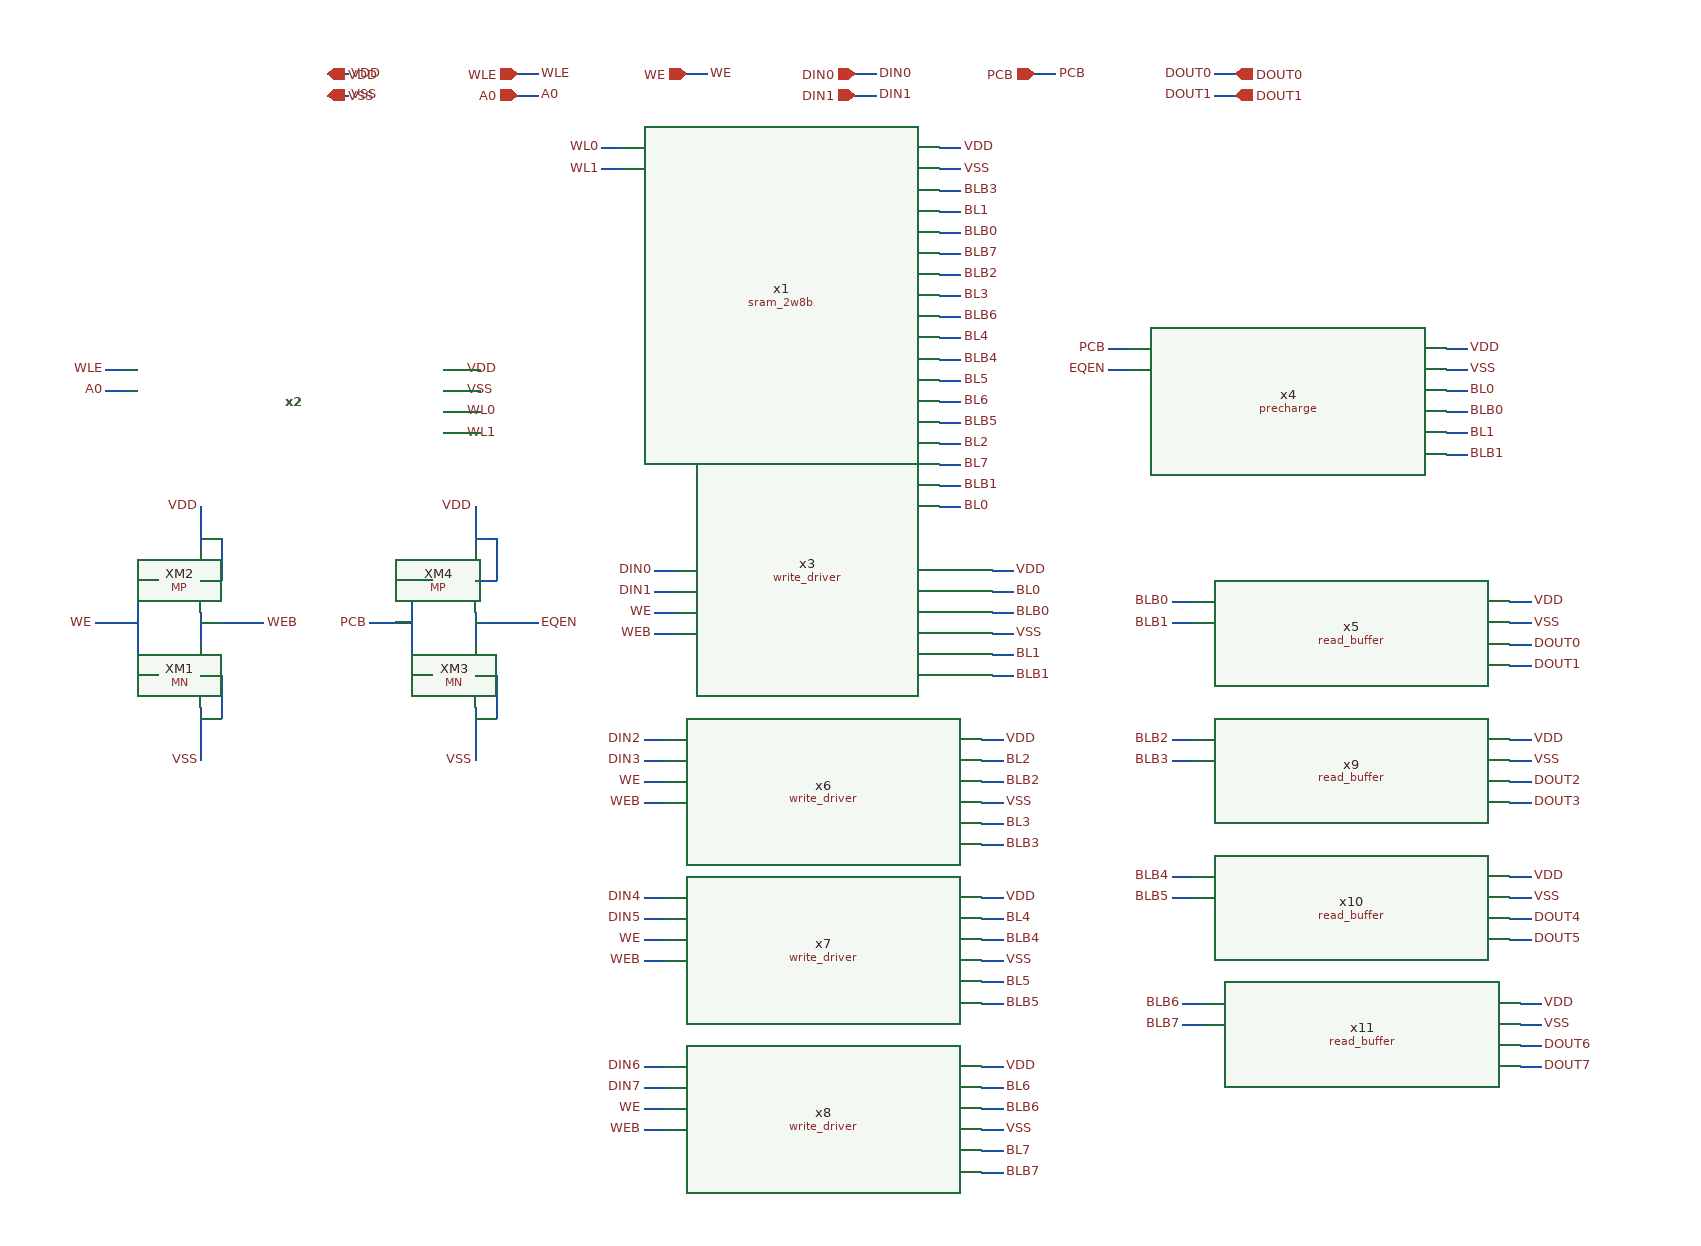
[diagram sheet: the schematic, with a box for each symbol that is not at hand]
v {xschem version=3.4.8RC file_version=1.3}
G {}
K {}
V {}
S {}
F {}
E {}
N 150 -410 170 -410 {lab=A0}
N 150 -430 170 -430 {lab=WLE}
N 470 -430 490 -430 {lab=VDD}
N 470 -410 490 -410 {lab=VSS}
N 470 -390 490 -390 {lab=WL0}
N 470 -370 490 -370 {lab=WL1}
N 620 -640 640 -640 {lab=WL0}
N 620 -620 640 -620 {lab=WL1}
N 940 -300 960 -300 {lab=BL0}
N 940 -580 960 -580 {lab=BL1}
N 940 -320 960 -320 {lab=BLB1}
N 940 -560 960 -560 {lab=BLB0}
N 1100 -450 1120 -450 {lab=PCB}
N 1100 -430 1120 -430 {lab=EQEN}
N 670 -240 690 -240 {lab=DIN0}
N 670 -220 690 -220 {lab=DIN1}
N 670 -200 690 -200 {lab=WE}
N 670 -180 690 -180 {lab=WEB}
N 990 -240 1010 -240 {lab=VDD}
N 990 -220 1010 -220 {lab=BL0}
N 990 -200 1010 -200 {lab=BLB0}
N 990 -180 1010 -180 {lab=VSS}
N 990 -160 1010 -160 {lab=BL1}
N 990 -140 1010 -140 {lab=BLB1}
N 1160 -210 1180 -210 {lab=BLB0}
N 1160 -190 1180 -190 {lab=BLB1}
N 1420 -450 1440 -450 {lab=VDD}
N 1420 -430 1440 -430 {lab=VSS}
N 1420 -410 1440 -410 {lab=BL0}
N 1420 -390 1440 -390 {lab=BLB0}
N 1420 -370 1440 -370 {lab=BL1}
N 1420 -350 1440 -350 {lab=BLB1}
N 1480 -210 1500 -210 {lab=VDD}
N 1480 -190 1500 -190 {lab=VSS}
N 1480 -170 1500 -170 {lab=DOUT0}
N 1480 -150 1500 -150 {lab=DOUT1}
N 360 -710 380 -710 {lab=VDD}
N 360 -690 380 -690 {lab=VSS}
N 540 -710 560 -710 {lab=WLE}
N 540 -690 560 -690 {lab=A0}
N 700 -710 720 -710 {lab=WE}
N 860 -710 880 -710 {lab=DIN0}
N 860 -690 880 -690 {lab=DIN1}
N 1030 -710 1050 -710 {lab=PCB}
N 1200 -710 1220 -710 {lab=DOUT0}
N 1200 -690 1220 -690 {lab=DOUT1}
N 240 -200 240 -170 {lab=WEB}
N 240 -110 240 -60 {lab=VSS}
N 240 -140 260 -140 {lab=VSS}
N 260 -140 260 -100 {lab=VSS}
N 240 -100 260 -100 {lab=VSS}
N 240 -300 240 -260 {lab=VDD}
N 180 -230 200 -230 {lab=WE}
N 180 -230 180 -140 {lab=WE}
N 180 -140 200 -140 {lab=WE}
N 240 -190 300 -190 {lab=WEB}
N 140 -190 180 -190 {lab=WE}
N 240 -230 260 -230 {lab=VDD}
N 260 -270 260 -230 {lab=VDD}
N 240 -270 260 -270 {lab=VDD}
N 500 -200 500 -170 {lab=EQEN}
N 500 -110 500 -60 {lab=VSS}
N 500 -140 520 -140 {lab=VSS}
N 520 -140 520 -100 {lab=VSS}
N 500 -100 520 -100 {lab=VSS}
N 500 -300 500 -260 {lab=VDD}
N 440 -230 460 -230 {lab=PCB}
N 440 -230 440 -140 {lab=PCB}
N 440 -140 460 -140 {lab=PCB}
N 500 -190 560 -190 {lab=EQEN}
N 400 -190 440 -190 {lab=PCB}
N 500 -230 520 -230 {lab=VDD}
N 520 -270 520 -230 {lab=VDD}
N 500 -270 520 -270 {lab=VDD}
N 940 -640 960 -640 {lab=VDD}
N 940 -620 960 -620 {lab=VSS}
N 940 -600 960 -600 {lab=BLB3}
N 940 -540 960 -540 {lab=BLB7}
N 940 -520 960 -520 {lab=BLB2}
N 940 -500 960 -500 {lab=BL3}
N 940 -480 960 -480 {lab=BLB6}
N 940 -460 960 -460 {lab=BL4}
N 940 -440 960 -440 {lab=BLB4}
N 940 -420 960 -420 {lab=BL5}
N 940 -400 960 -400 {lab=BL6}
N 940 -380 960 -380 {lab=BLB5}
N 940 -360 960 -360 {lab=BL2}
N 940 -340 960 -340 {lab=BL7}
N 660 -80 680 -80 {lab=DIN2}
N 660 -60 680 -60 {lab=DIN3}
N 660 -40 680 -40 {lab=WE}
N 660 -20 680 -20 {lab=WEB}
N 980 -80 1000 -80 {lab=VDD}
N 980 -60 1000 -60 {lab=BL2}
N 980 -40 1000 -40 {lab=BLB2}
N 980 -20 1000 -20 {lab=VSS}
N 980 0 1000 0 {lab=BL3}
N 980 20 1000 20 {lab=BLB3}
N 660 70 680 70 {lab=DIN4}
N 660 90 680 90 {lab=DIN5}
N 660 110 680 110 {lab=WE}
N 660 130 680 130 {lab=WEB}
N 980 70 1000 70 {lab=VDD}
N 980 90 1000 90 {lab=BL4}
N 980 110 1000 110 {lab=BLB4}
N 980 130 1000 130 {lab=VSS}
N 980 150 1000 150 {lab=BL5}
N 980 170 1000 170 {lab=BLB5}
N 660 230 680 230 {lab=DIN6}
N 660 250 680 250 {lab=DIN7}
N 660 270 680 270 {lab=WE}
N 660 290 680 290 {lab=WEB}
N 980 230 1000 230 {lab=VDD}
N 980 250 1000 250 {lab=BL6}
N 980 270 1000 270 {lab=BLB6}
N 980 290 1000 290 {lab=VSS}
N 980 310 1000 310 {lab=BL7}
N 980 330 1000 330 {lab=BLB7}
N 1160 -80 1180 -80 {lab=BLB2}
N 1160 -60 1180 -60 {lab=BLB3}
N 1480 -80 1500 -80 {lab=VDD}
N 1480 -60 1500 -60 {lab=VSS}
N 1480 -40 1500 -40 {lab=DOUT2}
N 1480 -20 1500 -20 {lab=DOUT3}
N 1160 50 1180 50 {lab=BLB4}
N 1160 70 1180 70 {lab=BLB5}
N 1480 50 1500 50 {lab=VDD}
N 1480 70 1500 70 {lab=VSS}
N 1480 90 1500 90 {lab=DOUT4}
N 1480 110 1500 110 {lab=DOUT5}
N 1170 170 1190 170 {lab=BLB6}
N 1170 190 1190 190 {lab=BLB7}
N 1490 170 1510 170 {lab=VDD}
N 1490 190 1510 190 {lab=VSS}
N 1490 210 1510 210 {lab=DOUT6}
N 1490 230 1510 230 {lab=DOUT1}
C {decoder.sym} 320 -400 0 0 {name=x2}
C {write_driver.sym} 840 -190 0 0 {name=x3}
C {precharge.sym} 1270 -400 0 0 {name=x4}
C {read_buffer.sym} 1330 -180 0 0 {name=x5}
C {devices/iopin.sym} 360 -710 0 1 {name=p1 lab=VDD}
C {devices/ipin.sym} 540 -710 0 0 {name=p2 lab=WLE}
C {devices/opin.sym} 1220 -710 0 0 {name=p3 lab=DOUT0}
C {devices/lab_pin.sym} 150 -430 0 0 {name=p5 sig_type=std_logic lab=WLE}
C {devices/lab_pin.sym} 150 -410 0 0 {name=p6 sig_type=std_logic lab=A0}
C {devices/lab_pin.sym} 490 -430 0 1 {name=p4 sig_type=std_logic lab=VDD}
C {devices/lab_pin.sym} 490 -410 0 1 {name=p7 sig_type=std_logic lab=VSS}
C {devices/lab_pin.sym} 490 -390 0 1 {name=p8 sig_type=std_logic lab=WL0}
C {devices/lab_pin.sym} 490 -370 0 1 {name=p9 sig_type=std_logic lab=WL1}
C {devices/lab_pin.sym} 620 -640 0 0 {name=p10 sig_type=std_logic lab=WL0}
C {devices/lab_pin.sym} 620 -620 0 0 {name=p11 sig_type=std_logic lab=WL1}
C {devices/lab_pin.sym} 960 -300 0 1 {name=p12 sig_type=std_logic lab=BL0}
C {devices/lab_pin.sym} 960 -580 0 1 {name=p14 sig_type=std_logic lab=BL1}
C {devices/lab_pin.sym} 960 -320 0 1 {name=p15 sig_type=std_logic lab=BLB1}
C {devices/lab_pin.sym} 960 -560 0 1 {name=p16 sig_type=std_logic lab=BLB0}
C {devices/lab_pin.sym} 1100 -450 0 0 {name=p17 sig_type=std_logic lab=PCB}
C {devices/lab_pin.sym} 1100 -430 0 0 {name=p18 sig_type=std_logic lab=EQEN}
C {devices/lab_pin.sym} 670 -240 0 0 {name=p19 sig_type=std_logic lab=DIN0}
C {devices/lab_pin.sym} 670 -220 0 0 {name=p20 sig_type=std_logic lab=DIN1}
C {devices/lab_pin.sym} 670 -200 0 0 {name=p21 sig_type=std_logic lab=WE}
C {devices/lab_pin.sym} 670 -180 0 0 {name=p22 sig_type=std_logic lab=WEB
}
C {devices/lab_pin.sym} 1010 -240 0 1 {name=p24 sig_type=std_logic lab=VDD}
C {devices/lab_pin.sym} 1010 -220 0 1 {name=p25 sig_type=std_logic lab=BL0}
C {devices/lab_pin.sym} 1010 -200 0 1 {name=p26 sig_type=std_logic lab=BLB0}
C {devices/lab_pin.sym} 1010 -180 0 1 {name=p27 sig_type=std_logic lab=VSS}
C {devices/lab_pin.sym} 1010 -160 0 1 {name=p28 sig_type=std_logic lab=BL1}
C {devices/lab_pin.sym} 1010 -140 0 1 {name=p29 sig_type=std_logic lab=BLB1}
C {devices/lab_pin.sym} 1160 -210 0 0 {name=p30 sig_type=std_logic lab=BLB0}
C {devices/lab_pin.sym} 1160 -190 0 0 {name=p31 sig_type=std_logic lab=BLB1}
C {devices/lab_pin.sym} 1440 -450 0 1 {name=p32 sig_type=std_logic lab=VDD}
C {devices/lab_pin.sym} 1440 -430 0 1 {name=p33 sig_type=std_logic lab=VSS}
C {devices/lab_pin.sym} 1440 -410 0 1 {name=p34 sig_type=std_logic lab=BL0}
C {devices/lab_pin.sym} 1440 -390 0 1 {name=p35 sig_type=std_logic lab=BLB0}
C {devices/lab_pin.sym} 1440 -370 0 1 {name=p36 sig_type=std_logic lab=BL1}
C {devices/lab_pin.sym} 1440 -350 0 1 {name=p37 sig_type=std_logic lab=BLB1}
C {devices/lab_pin.sym} 1500 -210 0 1 {name=p38 sig_type=std_logic lab=VDD}
C {devices/lab_pin.sym} 1500 -190 0 1 {name=p39 sig_type=std_logic lab=VSS}
C {devices/lab_pin.sym} 1500 -170 0 1 {name=p40 sig_type=std_logic lab=DOUT0}
C {devices/lab_pin.sym} 1500 -150 0 1 {name=p41 sig_type=std_logic lab=DOUT1}
C {devices/lab_pin.sym} 380 -710 0 1 {name=p42 sig_type=std_logic lab=VDD}
C {devices/iopin.sym} 360 -690 0 1 {name=p43 lab=VSS}
C {devices/lab_pin.sym} 380 -690 0 1 {name=p44 sig_type=std_logic lab=VSS}
C {devices/lab_pin.sym} 560 -710 0 1 {name=p45 sig_type=std_logic lab=WLE}
C {devices/ipin.sym} 540 -690 0 0 {name=p46 lab=A0}
C {devices/lab_pin.sym} 560 -690 0 1 {name=p47 sig_type=std_logic lab=A0}
C {devices/ipin.sym} 700 -710 0 0 {name=p48 lab=WE}
C {devices/lab_pin.sym} 720 -710 0 1 {name=p49 sig_type=std_logic lab=WE}
C {devices/ipin.sym} 860 -710 0 0 {name=p52 lab=DIN0}
C {devices/lab_pin.sym} 880 -710 0 1 {name=p53 sig_type=std_logic lab=DIN0}
C {devices/ipin.sym} 860 -690 0 0 {name=p54 lab=DIN1}
C {devices/lab_pin.sym} 880 -690 0 1 {name=p55 sig_type=std_logic lab=DIN1}
C {devices/ipin.sym} 1030 -710 0 0 {name=p56 lab=PCB}
C {devices/lab_pin.sym} 1050 -710 0 1 {name=p57 sig_type=std_logic lab=PCB}
C {devices/lab_pin.sym} 1200 -710 0 0 {name=p60 sig_type=std_logic lab=DOUT0}
C {devices/opin.sym} 1220 -690 0 0 {name=p61 lab=DOUT1}
C {devices/lab_pin.sym} 1200 -690 0 0 {name=p62 sig_type=std_logic lab=DOUT1}
C {devices/lab_pin.sym} 240 -300 0 0 {name=p63 sig_type=std_logic lab=VDD}
C {devices/lab_pin.sym} 140 -190 0 0 {name=p64 sig_type=std_logic lab=WE}
C {devices/lab_pin.sym} 300 -190 0 1 {name=p65 sig_type=std_logic lab=WEB}
C {devices/lab_pin.sym} 240 -60 0 0 {name=p66 sig_type=std_logic lab=VSS}
C {TR-1umLIB/MN.sym} 200 -140 0 0 {name=XM1
model=NMOS
w=3.4u
l=1u
m=1
spiceprefix=X
as=0
ad=0
ps=0
pd=0
nrd=0
nrs=0}
C {TR-1umLIB/MP.sym} 200 -230 0 0 {name=XM2
model=PMOS
w=6.8u
l=1u
m=1
spiceprefix=X
as=0
ad=0
ps=0
pd=0
nrd=0
nrs=0}
C {devices/lab_pin.sym} 500 -300 0 0 {name=p50 sig_type=std_logic lab=VDD}
C {devices/lab_pin.sym} 400 -190 0 0 {name=p51 sig_type=std_logic lab=PCB}
C {devices/lab_pin.sym} 560 -190 0 1 {name=p67 sig_type=std_logic lab=EQEN}
C {devices/lab_pin.sym} 500 -60 0 0 {name=p68 sig_type=std_logic lab=VSS}
C {TR-1umLIB/MN.sym} 460 -140 0 0 {name=XM3
model=NMOS
w=3.4u
l=1u
m=1
spiceprefix=X
as=0
ad=0
ps=0
pd=0
nrd=0
nrs=0}
C {TR-1umLIB/MP.sym} 460 -230 0 0 {name=XM4
model=PMOS
w=6.8u
l=1u
m=1
spiceprefix=X
as=0
ad=0
ps=0
pd=0
nrd=0
nrs=0}
C {/home/take/Design/tr10_sram/array/2word_x_8bit/sram_2w8b.sym} 790 -470 0 0 {name=x1}
C {devices/lab_pin.sym} 960 -640 0 1 {name=p58 sig_type=std_logic lab=VDD}
C {devices/lab_pin.sym} 960 -620 0 1 {name=p59 sig_type=std_logic lab=VSS}
C {devices/lab_pin.sym} 960 -600 0 1 {name=p13 sig_type=std_logic lab=BLB3}
C {devices/lab_pin.sym} 960 -540 0 1 {name=p23 sig_type=std_logic lab=BLB7}
C {devices/lab_pin.sym} 960 -520 0 1 {name=p69 sig_type=std_logic lab=BLB2}
C {devices/lab_pin.sym} 960 -500 0 1 {name=p70 sig_type=std_logic lab=BL3}
C {devices/lab_pin.sym} 960 -480 0 1 {name=p71 sig_type=std_logic lab=BLB6}
C {devices/lab_pin.sym} 960 -460 0 1 {name=p72 sig_type=std_logic lab=BL4}
C {devices/lab_pin.sym} 960 -440 0 1 {name=p73 sig_type=std_logic lab=BLB4}
C {devices/lab_pin.sym} 960 -420 0 1 {name=p74 sig_type=std_logic lab=BL5}
C {devices/lab_pin.sym} 960 -400 0 1 {name=p75 sig_type=std_logic lab=BL6}
C {devices/lab_pin.sym} 960 -380 0 1 {name=p76 sig_type=std_logic lab=BLB5}
C {devices/lab_pin.sym} 960 -360 0 1 {name=p77 sig_type=std_logic lab=BL2}
C {devices/lab_pin.sym} 960 -340 0 1 {name=p78 sig_type=std_logic lab=BL7}
C {write_driver.sym} 830 -30 0 0 {name=x6}
C {devices/lab_pin.sym} 660 -80 0 0 {name=p79 sig_type=std_logic lab=DIN2}
C {devices/lab_pin.sym} 660 -60 0 0 {name=p80 sig_type=std_logic lab=DIN3}
C {devices/lab_pin.sym} 660 -40 0 0 {name=p81 sig_type=std_logic lab=WE}
C {devices/lab_pin.sym} 660 -20 0 0 {name=p82 sig_type=std_logic lab=WEB
}
C {devices/lab_pin.sym} 1000 -80 0 1 {name=p83 sig_type=std_logic lab=VDD}
C {devices/lab_pin.sym} 1000 -60 0 1 {name=p84 sig_type=std_logic lab=BL2}
C {devices/lab_pin.sym} 1000 -40 0 1 {name=p85 sig_type=std_logic lab=BLB2}
C {devices/lab_pin.sym} 1000 -20 0 1 {name=p86 sig_type=std_logic lab=VSS}
C {devices/lab_pin.sym} 1000 0 0 1 {name=p87 sig_type=std_logic lab=BL3}
C {devices/lab_pin.sym} 1000 20 0 1 {name=p88 sig_type=std_logic lab=BLB3}
C {write_driver.sym} 830 120 0 0 {name=x7}
C {devices/lab_pin.sym} 660 70 0 0 {name=p91 sig_type=std_logic lab=DIN4}
C {devices/lab_pin.sym} 660 90 0 0 {name=p92 sig_type=std_logic lab=DIN5}
C {devices/lab_pin.sym} 660 110 0 0 {name=p93 sig_type=std_logic lab=WE}
C {devices/lab_pin.sym} 660 130 0 0 {name=p94 sig_type=std_logic lab=WEB
}
C {devices/lab_pin.sym} 1000 70 0 1 {name=p95 sig_type=std_logic lab=VDD}
C {devices/lab_pin.sym} 1000 90 0 1 {name=p96 sig_type=std_logic lab=BL4}
C {devices/lab_pin.sym} 1000 110 0 1 {name=p97 sig_type=std_logic lab=BLB4}
C {devices/lab_pin.sym} 1000 130 0 1 {name=p98 sig_type=std_logic lab=VSS}
C {devices/lab_pin.sym} 1000 150 0 1 {name=p99 sig_type=std_logic lab=BL5}
C {devices/lab_pin.sym} 1000 170 0 1 {name=p100 sig_type=std_logic lab=BLB5}
C {write_driver.sym} 830 280 0 0 {name=x8}
C {devices/lab_pin.sym} 660 230 0 0 {name=p103 sig_type=std_logic lab=DIN6}
C {devices/lab_pin.sym} 660 250 0 0 {name=p104 sig_type=std_logic lab=DIN7}
C {devices/lab_pin.sym} 660 270 0 0 {name=p105 sig_type=std_logic lab=WE}
C {devices/lab_pin.sym} 660 290 0 0 {name=p106 sig_type=std_logic lab=WEB
}
C {devices/lab_pin.sym} 1000 230 0 1 {name=p107 sig_type=std_logic lab=VDD}
C {devices/lab_pin.sym} 1000 250 0 1 {name=p108 sig_type=std_logic lab=BL6}
C {devices/lab_pin.sym} 1000 270 0 1 {name=p109 sig_type=std_logic lab=BLB6}
C {devices/lab_pin.sym} 1000 290 0 1 {name=p110 sig_type=std_logic lab=VSS}
C {devices/lab_pin.sym} 1000 310 0 1 {name=p111 sig_type=std_logic lab=BL7}
C {devices/lab_pin.sym} 1000 330 0 1 {name=p112 sig_type=std_logic lab=BLB7}
C {read_buffer.sym} 1330 -50 0 0 {name=x9}
C {devices/lab_pin.sym} 1160 -80 0 0 {name=p89 sig_type=std_logic lab=BLB2}
C {devices/lab_pin.sym} 1160 -60 0 0 {name=p90 sig_type=std_logic lab=BLB3}
C {devices/lab_pin.sym} 1500 -80 0 1 {name=p101 sig_type=std_logic lab=VDD}
C {devices/lab_pin.sym} 1500 -60 0 1 {name=p102 sig_type=std_logic lab=VSS}
C {devices/lab_pin.sym} 1500 -40 0 1 {name=p113 sig_type=std_logic lab=DOUT2}
C {devices/lab_pin.sym} 1500 -20 0 1 {name=p114 sig_type=std_logic lab=DOUT3}
C {read_buffer.sym} 1330 80 0 0 {name=x10}
C {devices/lab_pin.sym} 1160 50 0 0 {name=p115 sig_type=std_logic lab=BLB4}
C {devices/lab_pin.sym} 1160 70 0 0 {name=p116 sig_type=std_logic lab=BLB5}
C {devices/lab_pin.sym} 1500 50 0 1 {name=p117 sig_type=std_logic lab=VDD}
C {devices/lab_pin.sym} 1500 70 0 1 {name=p118 sig_type=std_logic lab=VSS}
C {devices/lab_pin.sym} 1500 90 0 1 {name=p119 sig_type=std_logic lab=DOUT4}
C {devices/lab_pin.sym} 1500 110 0 1 {name=p120 sig_type=std_logic lab=DOUT5}
C {read_buffer.sym} 1340 200 0 0 {name=x11}
C {devices/lab_pin.sym} 1170 170 0 0 {name=p121 sig_type=std_logic lab=BLB6}
C {devices/lab_pin.sym} 1170 190 0 0 {name=p122 sig_type=std_logic lab=BLB7}
C {devices/lab_pin.sym} 1510 170 0 1 {name=p123 sig_type=std_logic lab=VDD}
C {devices/lab_pin.sym} 1510 190 0 1 {name=p124 sig_type=std_logic lab=VSS}
C {devices/lab_pin.sym} 1510 210 0 1 {name=p125 sig_type=std_logic lab=DOUT6}
C {devices/lab_pin.sym} 1510 230 0 1 {name=p126 sig_type=std_logic lab=DOUT7}
